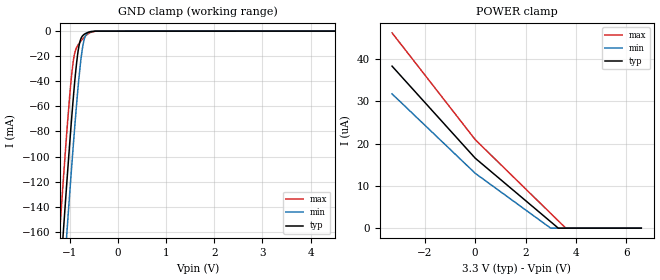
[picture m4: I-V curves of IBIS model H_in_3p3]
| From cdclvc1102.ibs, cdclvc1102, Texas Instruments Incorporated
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|   H_in_3p3
[Model]   H_in_3p3
|Signal:   CLK_IN
Model_type   Input
Vinl   = 1.05
Vinh   = 2.25
|   typ   min   max
C_comp   1.095p   0.8876p   1.267p
[Voltage Range]   3.3   3   3.6
[Temperature Range]   25   85   -40
[Power Clamp Reference]   3.3   3   3.6
[GND Clamp Reference]   0   0   0
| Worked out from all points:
|   GND clamp passes 1 mA (typ) near -0.62 V on its own axis
[GND Clamp]
|   Voltage   I(typ)   I(min)   I(max)
-3.3V     -1.461A    -1.498A    -1.424A
-1.221V   -205.2mA   -246.6mA   -163.1mA
-1.206V   -196.8mA   -238.2mA   -154.8mA
-1.137V   -158.3mA   -199.5mA   -116.8mA
-1.063V   -118.2mA   -158.8mA   -77.89mA
-993.3mV  -82.32mA   -121.9mA   -45.28mA
-933.9mV  -53.77mA   -91.51mA   -24.12mA
-834.9mV  -16.51mA   -45.38mA   -11.08mA
-790.3mV  -7.815mA   -28.03mA   -8.678mA
-730.9mV  -3.383mA   -11.06mA   -5.934mA
-632mV    -1.136mA   -1.243mA   -2.365mA
6.6V      0A         0A         0A
[POWER Clamp]
|   Voltage   I(typ)   I(min)   I(max)
-3.3V     38.35uA    31.78uA    46.23uA
1.65mV    16.57uA    12.99uA    20.96uA
3.001V    1.515uA    0A         3.489uA
3.303V    0A         0A         1.73uA
3.6V      0A         0A         0A
6.6V      0A         0A         0A
